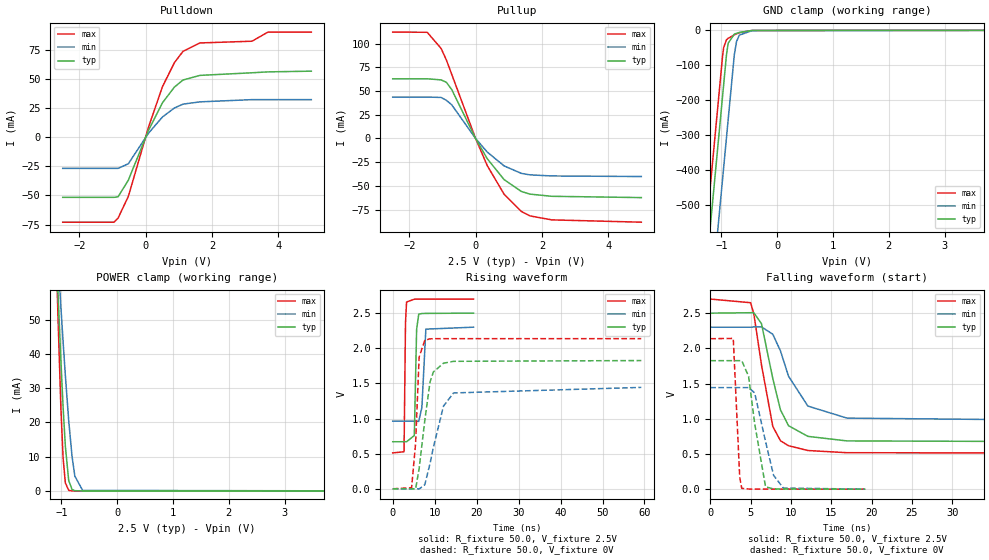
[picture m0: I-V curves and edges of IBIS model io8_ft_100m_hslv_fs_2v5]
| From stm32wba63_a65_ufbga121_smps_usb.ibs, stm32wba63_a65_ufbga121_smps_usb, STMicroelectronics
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[Model]   io8_ft_100m_hslv_fs_2v5
Model_type I/O
Polarity   Non-Inverting
Enable   Active-Low
| CAP_THRESHOLD on pad IOFT is "UDTCAPC" :
| Rising=30.0% of vddiom   Falling=70.0% of vddiom
| C_comp min and max val. don't necessarily correlate with the min and max pvt
| but are the smallest and greatest pad capacitance found.
| var   typ   min   max
C_comp   3.76306pF  3.70263pF  3.86856pF
|C_comp_pullup   2.23792pF  2.13266pF  2.37573pF
|C_comp_pulldown   1.52514pF  1.56997pF  1.49284pF
Vinl = 1.15V
Vinh = 1.35V
Vmeas = 1.25V   | Reference voltage for timing measurements
Cref  = 50.0pF   | Timing specification test load capacitance value
Rref  = 1.0MOhm   | Timing specification test load resistance value
Vref  = 1.375V   | Timing specification test load voltage
[Model Spec]
| TIME_THRESHOLD on pin ZIV11 is "CMOS" :
| Rising=50.0% of vdd   Falling=50.0% of vdd
Vinl 992.50000mV 921.50000mV 1.05850V
Vinh 1.43350V 1.32250V 1.51250V
| variable   typ   min   max
[Temperature Range] 25.0 140.0 -40.0
| variable   typ   min   max
[Voltage Range] 2.5V 2.3V 2.7V
| variable   typ   min   max
[POWER Clamp Reference] 2.5V 2.3V 2.7V
| variable   typ   min   max
[GND Clamp Reference] 0V 0V 0V
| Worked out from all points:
|   slope of the pulldown table from 0 to 0.375 V, typ, clamps not added: 16.2 ohm
|   slope of the pullup table from 0 to 0.375 V, typ, clamps not added: 16.7 ohm
|   GND clamp passes 1 mA (typ) near -0.51 V on its own axis
|   POWER clamp passes 1 mA (typ) near -0.83 V on its own axis
|   rising waveform, R_fixture 50.0, V_fixture 2.5V: 20-80 % time 289ps typ, 442ps min, 213ps max; typ from 0.67 V to 2.5 V
|   falling waveform, R_fixture 50.0, V_fixture 2.5V: 20-80 % time 2.31ns typ, 3.15ns min, 1.95ns max; typ from 2.5 V to 0.67 V
|   rising waveform, R_fixture 50.0, V_fixture 0V: 20-80 % time 2.24ns typ, 3.38ns min, 1.04ns max; typ from 0 V to 1.82 V
|   falling waveform, R_fixture 50.0, V_fixture 0V: 20-80 % time 1.17ns typ, 1.57ns min, 454ps max; typ from 1.82 V to 0 V
[POWER Clamp]
-2.5V     733.7mA    502.6mA    1.062A
-1.09V    69.42mA    75.17mA    67.14mA
-1.08V    65.31mA    72.42mA    61.23mA
-1.06V    57.23mA    66.98mA    49.77mA
-1.01V    38.06mA    53.68mA    24.29mA
-970mV    24.36mA    43.46mA    9.575mA
-930mV    13.06mA    33.74mA    2.352mA
-870mV    3.065mA    20.56mA    165.9uA
-810mV    418.4uA    10.06mA    10.3uA
-760mV    69.41uA    4.321mA    1.008uA
-620mV    424.8nA    151.9uA    1.655nA
5V        0A         0A         0A
[GND Clamp]
-2.5V     -2.774A    -3.011A    -2.658A
-1.45V    -988.6mA   -1.226A    -873.4mA
-1.21V    -580.6mA   -818.3mA   -465.4mA
-980mV    -189.6mA   -427.3mA   -74.41mA
-960mV    -155.6mA   -393.3mA   -49.14mA
-910mV    -70.61mA   -308.3mA   -27.43mA
-880mV    -37.05mA   -257.3mA   -22.95mA
-770mV    -11.2mA    -71.03mA   -13.02mA
-730mV    -8.651mA   -32.36mA   -10.11mA
-680mV    -6.129mA   -13.76mA   -6.945mA
-450mV    -356.3uA   -840.3uA   -213.1uA
5V        1.758nA    357.7nA    738.1pA
| variable   typ   min   max
[Pullup Reference] 2.5V 2.3V 2.7V
| variable   typ   min   max
[Pulldown Reference] 0V 0V 0V
[Pullup]
-2.5V     62.88mA    43.62mA    112.1mA
-1.46V    62.88mA    43.62mA    111.9mA
-1.04V    61.71mA    43.22mA    94.87mA
-880mV    59.16mA    40.17mA    82.61mA
-720mV    51.57mA    35.47mA    67.6mA
0V        692.6fA    264.9pA    3.85fA
350mV     -21.24mA   -14.26mA   -28.5mA
860mV     -43.37mA   -28.93mA   -58.75mA
1.38V     -55.84mA   -36.8mA    -76.9mA
1.64V     -58.66mA   -38.36mA   -81.62mA
2.3V      -60.96mA   -39.52mA   -85.81mA
5V        -62.33mA   -40.13mA   -88.25mA
[Pulldown]
-2.5V     -51.61mA   -26.66mA   -73.01mA
-950mV    -51.61mA   -26.66mA   -73.01mA
-830mV    -51.13mA   -26.66mA   -69.5mA
-520mV    -36.86mA   -22.67mA   -50.81mA
90mV      6.214mA    3.696mA    8.997mA
510mV     29.86mA    17.62mA    43.74mA
870mV     43.36mA    25.34mA    64.34mA
1.13V     49.44mA    28.66mA    74.15mA
1.64V     53.42mA    30.62mA    81.36mA
3.21V     55.67mA    32.54mA    82.85mA
3.69V     56.44mA    32.54mA    90.68mA
5V        57.06mA    32.54mA    90.71mA
[Ramp]
dV/dt_r 1.09519V/2.21901ns 865.98144mV/3.35371ns 1.28201V/1.03819ns
dV/dt_f 1.09819V/2.19634ns 802.23203mV/3.06287ns 1.31366V/1.95231ns
R_load = 50.0
| Removed startup time: 0s 0s 0s  .
| Removed end time: 19.25ns.
[Rising Waveform]
R_fixture   = 50.0
V_fixture   = 2.5V
V_fixture_min = 2.3V
V_fixture_max = 2.7V
0s        669.7mV    962.9mV    510.6mV
2.7ns     669.7mV    962.9mV    527.3mV
3.05ns    669.7mV    962.9mV    2.363V
3.3ns     669.7mV    962.9mV    2.658V
5.15ns    758.4mV    963mV      2.698V
5.7ns     2.269V     962.6mV    2.699V
6.2ns     2.484V     959.2mV    2.7V
6.95ns    2.494V     1.155V     2.7V
7.9ns     2.496V     2.272V     2.7V
19.25ns   2.5V       2.3V       2.7V
| Removed startup time: 0s 0s 0s  .
| Removed end time: 59.25ns.
[Falling Waveform]
R_fixture   = 50.0
V_fixture   = 2.5V
V_fixture_min = 2.3V
V_fixture_max = 2.7V
0s        2.5V       2.3V       2.7V
5ns       2.506V     2.3V       2.648V
5.4ns     2.505V     2.305V     2.49V
6.35ns    2.35V      2.305V     1.764V
7.75ns    1.571V     2.2V       891.2mV
8.7ns     1.127V     1.964V     687.7mV
9.7ns     901.1mV    1.604V     616.7mV
12.1ns    749.9mV    1.18V      548.9mV
16.95ns   685.3mV    1.009V     517.9mV
59.25ns   669.7mV    962.9mV    510.6mV
| Removed startup time: 0s 0s 0s  .
| Removed end time: 59.25ns.
[Rising Waveform]
R_fixture   = 50.0
V_fixture   = 0V
V_fixture_min = 0V
V_fixture_max = 0V
0s        5.305nV    128.7nV    4.788nV
4.5ns     34.17uV    2.403uV    15.51mV
5.45ns    -5.193mV   47.04uV    641.9mV
6.3ns     289.7mV    -2.999mV   1.875V
7.65ns    973.3mV    57.72mV    2.115V
8.9ns     1.522V     361.2mV    2.134V
9.7ns     1.663V     591.1mV    2.136V
12.1ns    1.787V     1.177V     2.137V
14.5ns    1.814V     1.364V     2.137V
59.25ns   1.825V     1.443V     2.137V
| Removed startup time: 0s 0s 0s  .
| Removed end time: 19.2ns.
[Falling Waveform]
R_fixture   = 50.0
V_fixture   = 0V
V_fixture_min = 0V
V_fixture_max = 0V
0s        1.825V     1.443V     2.137V
2.85ns    1.825V     1.443V     2.141V
3.65ns    1.825V     1.443V     171.6mV
3.9ns     1.826V     1.443V     11.82mV
4.75ns    1.602V     1.443V     2.213mV
5.5ns     935.8mV    1.368V     1.284mV
6.85ns    33.81mV    676.4mV    463.4uV
7.85ns    2.623mV    195.6mV    228.6uV
9.05ns    1.335mV    16.04mV    108.4uV
19.2ns    71.25uV    164.8uV    2.218uV
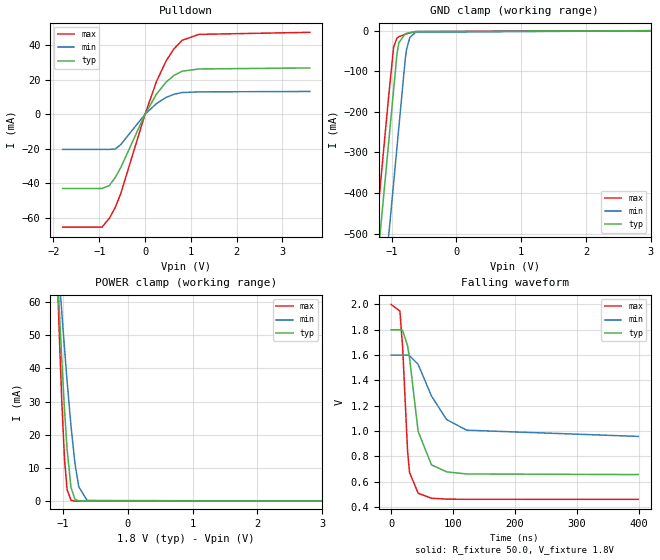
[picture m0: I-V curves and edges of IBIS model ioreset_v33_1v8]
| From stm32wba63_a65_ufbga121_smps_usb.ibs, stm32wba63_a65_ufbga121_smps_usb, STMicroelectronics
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[Model]   ioreset_v33_1v8
Model_type I/O_open_drain
Polarity   Inverting
Enable   Active-Low
| CAP_THRESHOLD on pad IOFT is "UDTCAPC" :
| Rising=30.0% of vddiom   Falling=70.0% of vddiom
| C_comp min and max val. don't necessarily correlate with the min and max pvt
| but are the smallest and greatest pad capacitance found.
| var   typ   min   max
C_comp   2.38285pF  2.34626pF  2.46409pF
|C_comp_pulldown   2.38285pF  2.34626pF  2.46409pF
Vinl = 800.0mV
Vinh = 1.0V
Vmeas = 900.0mV   | Reference voltage for timing measurements
Cref  = 50.0pF   | Timing specification test load capacitance value
Rref  = 1.0MOhm   | Timing specification test load resistance value
Vref  = 990.0mV   | Timing specification test load voltage
[Model Spec]
| TIME_THRESHOLD on pin ZIV33M is "CMOS" :
| Rising=50.0% of vddiom   Falling=50.0% of vddiom
Vinl 700.50000mV 623.50000mV 785.50000mV
Vinh 1.08250V 952.50000mV 1.18950V
| variable   typ   min   max
[Temperature Range] 25.0 140.0 -40.0
| variable   typ   min   max
[Voltage Range] 1.8V 1.6V 2.0V
| variable   typ   min   max
[POWER Clamp Reference] 1.8V 1.6V 2.0V
| variable   typ   min   max
[GND Clamp Reference] 0V 0V 0V
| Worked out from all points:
|   slope of the pulldown table from 0 to 0.27 V, typ, clamps not added: 21.9 ohm
|   GND clamp passes 1 mA (typ) near -0.54 V on its own axis
|   POWER clamp passes 1 mA (typ) near -0.83 V on its own axis
|   falling waveform, R_fixture 50.0, V_fixture 1.8V: 20-80 % time 18.4ns typ, 41.1ns min, 9.68ns max; typ from 1.8 V to 0.655 V
[POWER Clamp]
-1.8V     396.4mA    285.5mA    556.9mA
-1.09V    69.42mA    75.17mA    67.14mA
-1.08V    65.31mA    72.42mA    61.23mA
-1.06V    57.23mA    66.98mA    49.77mA
-1.02V    41.75mA    56.3mA     28.91mA
-980mV    27.6mA     45.97mA    12.6mA
-940mV    15.59mA    36.11mA    3.485mA
-880mV    4.091mA    22.61mA    262.5uA
-820mV    594.6uA    11.56mA    16.39uA
-760mV    69.41uA    4.321mA    1.008uA
-630mV    611nA      197.1uA    2.436nA
3.6V      0A         0A         0A
[GND Clamp]
-1.8V     -1.557A    -1.787A    -1.443A
-1.43V    -927.8mA   -1.158A    -814.3mA
-1.24V    -604.8mA   -834.8mA   -491.3mA
-1.05V    -281.8mA   -511.8mA   -168.3mA
-970mV    -145.8mA   -375.8mA   -41.08mA
-920mV    -60.81mA   -290.8mA   -19.17mA
-890mV    -30.35mA   -239.8mA   -15.33mA
-790mV    -8.014mA   -70.37mA   -9.121mA
-770mV    -6.959mA   -46.41mA   -8.135mA
-720mV    -5.009mA   -17.37mA   -5.886mA
-630mV    -2.532mA   -4.263mA   -2.711mA
3.6V      390.2pA    26.69nA    261.4pA
| variable   typ   min   max
[Pullup Reference] 1.8V 1.6V 2.0V
| variable   typ   min   max
[Pulldown Reference] 0V 0V 0V
[Pulldown]
-1.8V     -42.95mA   -20.33mA   -65.32mA
-940mV    -42.95mA   -20.33mA   -65.28mA
-780mV    -41.28mA   -20.33mA   -60.22mA
-650mV    -36.56mA   -20.09mA   -53.9mA
-530mV    -30.84mA   -17.53mA   -45.86mA
0V        0A         1.01fA     0A
250mV     11.65mA    6.197mA    19.01mA
460mV     18.61mA    9.735mA    30.85mA
630mV     22.46mA    11.56mA    37.82mA
810mV     24.92mA    12.58mA    42.8mA
1.18V     26.22mA    12.97mA    46.24mA
3.6V      26.81mA    13.2mA     47.42mA
[Ramp]
dV/dt_r 688.48202mV/314.35762ps 385.91292mV/624.85708ps 915.66877mV/205.54576ps
dV/dt_f 687.01104mV/18.33538ns 385.90099mV/40.88348ns 924.47531mV/9.32952ns
R_load = 50.0
| Removed startup time: 0s 0s 0s  .
| Removed end time: 99.99us.
|[Rising Waveform]
|R_fixture   = 50.0
|V_fixture   = 1.8V
|V_fixture_min = 1.6V
|V_fixture_max = 2.0V
|  0s  654.98159mV  956.81124mV  459.20781mV
|  10.0ns  654.98158mV  956.81123mV  459.20781mV
|  2.04us  654.98158mV  956.81123mV  459.20781mV
|  4.08us  654.98158mV  956.81123mV  459.20781mV
|  6.12us  654.98158mV  956.81123mV  459.20781mV
|  8.16us  654.98158mV  956.81123mV  459.20781mV
|  10.2us  654.98158mV  956.81123mV  459.20781mV
|  12.24us  654.98158mV  956.81123mV  459.20781mV
|  14.29us  654.98158mV  956.81123mV  459.20781mV
|  16.33us  654.98158mV  956.81123mV  459.20781mV
|  18.37us  654.98158mV  956.81123mV  459.20781mV
|  20.41us  654.98158mV  956.81123mV  459.20781mV
|  22.45us  654.98158mV  956.81123mV  459.20781mV
|  24.49us  654.98158mV  956.81123mV  459.20781mV
|  25.02us  654.98158mV  956.81123mV  459.20781mV
|  26.53us  654.98158mV  956.81123mV  459.20781mV
|  28.57us  654.98158mV  956.81123mV  459.20781mV
|  30.61us  654.98158mV  956.81123mV  459.20781mV
|  32.65us  654.98158mV  956.81123mV  459.20781mV
|  32.92us  654.98158mV  956.81123mV  459.20781mV
|  33.1us  654.98158mV  956.81123mV  459.20781mV
|  33.12us  654.98158mV  956.81123mV  459.20781mV
|  33.16us  654.98158mV  956.81123mV  459.20781mV
|  33.18us  654.98158mV  956.81123mV  459.20781mV
|  33.26us  654.98158mV  956.81123mV  459.20781mV
|  33.27us  654.98158mV  956.81123mV  459.20781mV
|  33.28us  654.98158mV  956.81123mV  459.20781mV
|  33.29us  654.98158mV  956.81123mV  459.20781mV
|  33.3us  654.98158mV  956.81123mV  459.20781mV
|  33.31us  654.98158mV  956.81123mV  459.20781mV
|  33.32us  654.98158mV  956.81123mV  459.20781mV
|  33.47us  654.98158mV  956.81123mV  459.20781mV
|  33.48us  654.98158mV  956.81123mV  459.20781mV
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[Falling Waveform]
R_fixture   = 50.0
V_fixture   = 1.8V
V_fixture_min = 1.6V
V_fixture_max = 2.0V
0s        1.8V       1.6V       2V
14.25ns   1.8V       1.6V       1.949V
18.65ns   1.795V     1.6V       1.663V
26.65ns   1.674V     1.6V       841.3mV
29.75ns   1.58V      1.595V     673.1mV
43.7ns    996.8mV    1.527V     507.4mV
65.2ns    732mV      1.277V     467.9mV
89.65ns   676.6mV    1.09V      460.7mV
122.2ns   659.6mV    1.006V     459.3mV
399.3ns   655mV      956.8mV    459.2mV
